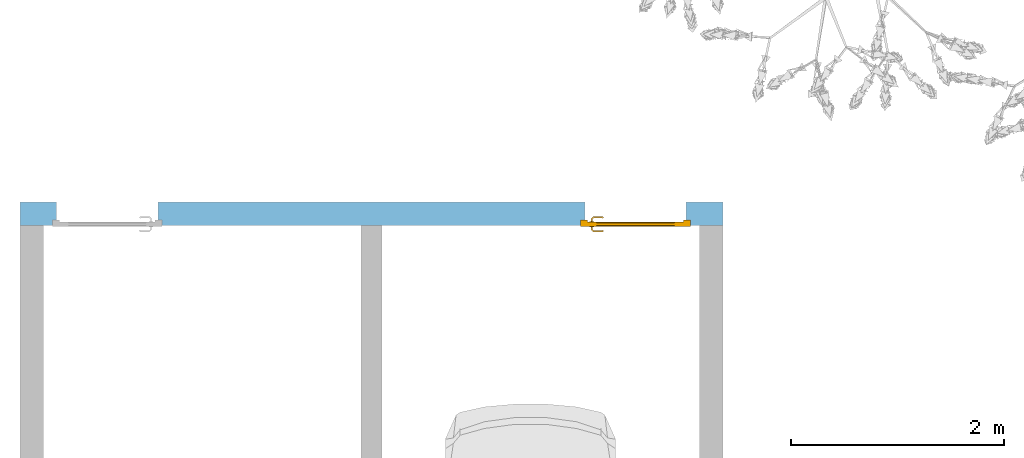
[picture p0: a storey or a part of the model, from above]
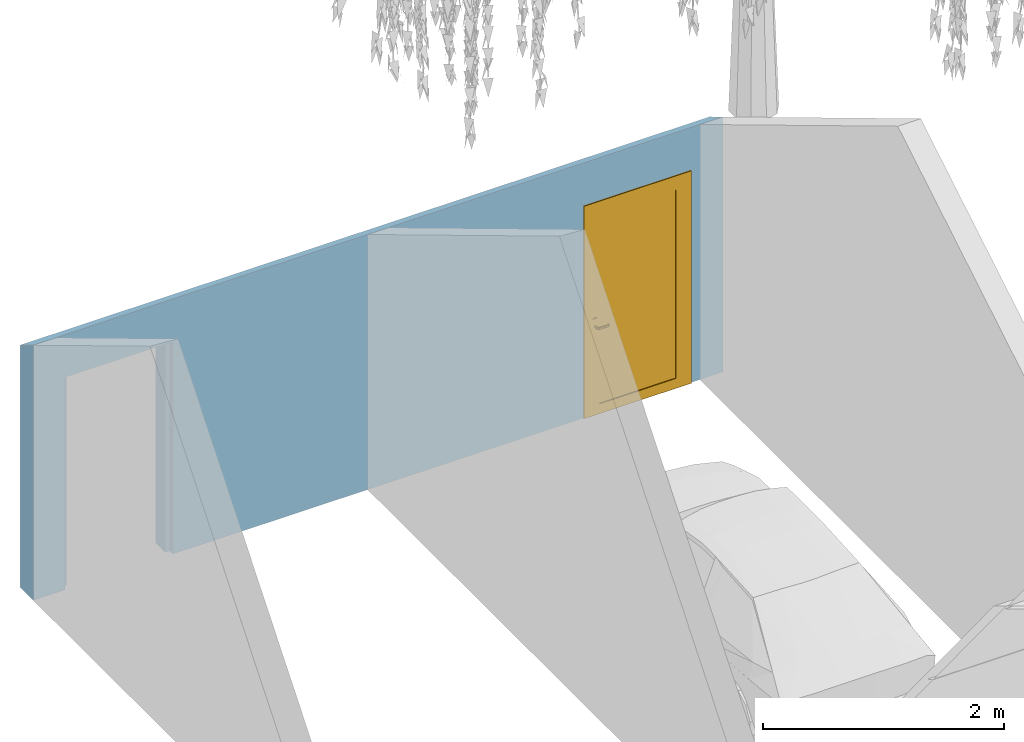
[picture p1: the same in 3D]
Properties of the parts of a building model (IFC2X3)

# File
Description: ViewDefinition [CoordinationView_V2.0]
Time: 2016-03-02T06:42:50
Written by: The EXPRESS Data Manager Version 5.02.0100.07 : 28 Aug 2013
Made in: 20150714_1515(x64) - Exporter 16.3.0.0 - Interface alternative d'export 16.3.0.0
Comment: STEP Physical File produced by: The EXPRESS Data Manager Version 5.02.0100.07 : 28 Aug 2013 * Module: EDMstepFileFactory/EDMstandAlone * Creation date: Wed Mar 02 06:42:50 2016 * Host: St�phaneBertran * Database: C:\Users\STPHAN~1\AppData\Local\Temp\{C8C356D1-8ECD-40BC-B914-F6F8F303F9F7}\ifc * Database version: 5507 * Database creation date: Wed Mar 02 06:42:32 2016 * Schema: IFC2X3 * Model: DataRepository.ifc * Model creation date: Wed Mar 02 06:42:33 2016 * Header model: DataRepository.ifc_HeaderModel * Header model creation date: Wed Mar 02 06:42:33 2016 * EDMuser: sdai-user * EDMgroup: sdai-group * License ID and type: 5605 : Permanent license. Expiry date: * EDMstepFileFactory options: 020000

# IfcProject
LongName: 2 garages

# IfcSite, Surface:224469
RefLatitude: 48, 51, 23, 999633; RefLongitude: 2, 21, 3, 553905; RefElevation: 0 m

# IfcBuilding
Pset_BuildingCommon - NumberOfStoreys: 3

# IfcBuildingStorey (3)
Name | LongName | Elevation (m)
Plan de soubassement | Plan de soubassement | -0.75
Plan du rez de chaussée | Plan du rez de chaussée | 0
Niveau 1 | Niveau 1 | 2.45

# IfcSpace (2)
In: Plan du rez de chaussée
InteriorOrExteriorSpace: INTERNAL
Name | LongName | Reference
1 | Garage 1 | Garage 1 1
2 | Garage 2 | Garage 2 2

# IfcBuildingElementProxy: Bicycle01, Bicycle01:Bicycle01:227164
In: Plan du rez de chaussée
Pset_BuildingElementProxyCommon - Reference: Bicycle01

# IfcBuildingElementProxy: Car01, Car01:Car01:226481
In: 1
Pset_BuildingElementProxyCommon - Reference: Car01

# IfcBuildingElementProxy: Saule pleureur - 6 m, Arbre 3D - Saule pleureur:Saule pleureur - 6 m:225890
In: Plan du rez de chaussée
Pset_BuildingElementProxyCommon - Reference: Saule pleureur - 6 m

# IfcDoor: 93 x 210 - (90), FR_PVC Panneau Plein:93 x 210 - (90):216726
In: Plan du rez de chaussée
Type - OperationType: SINGLE_SWING_LEFT; ParameterTakesPrecedence: no; Sizeable: no; Material: Poignée PVC, PVC Blanc
Type - FR_PVC Panneau Plein:93 x 210 - (90):216726 - PanelOperation: SWINGING
OverallHeight: 2.15 m; OverallWidth: 1.03 m
Pset_DoorCommon - IsExternal: no; Reference: 93 x 210 - (90)

# IfcDoor: 93 x 210 - (90), FR_PVC Panneau Plein:93 x 210 - (90):216636
In: Plan du rez de chaussée
Type - OperationType: SINGLE_SWING_RIGHT; ParameterTakesPrecedence: no; Sizeable: no; Material: Poignée PVC, PVC Blanc
Type - FR_PVC Panneau Plein:93 x 210 - (90):216636 - PanelOperation: SWINGING
OverallHeight: 2.15 m; OverallWidth: 1.03 m
Pset_DoorCommon - IsExternal: no; Reference: 93 x 210 - (90)

# IfcDoor: 96" x 78" (2)
In: Plan du rez de chaussée
Type - ParameterTakesPrecedence: no; Sizeable: no; Classification: B2030410 Overhead Doors (Uniformat); Material: Rubber - Black
OverallHeight: 1.9812 m; OverallWidth: 2.4384 m
Pset_DoorCommon - Reference: 96" x 78"; IsExternal: no
Name (Overhead-Sectional-Flush:96" x 78":...)
216232
216340

# IfcRoof: Toit de base:Toit - 100 mm 2, Toit de base:Toit - 100 mm 2:216761
In: Niveau 1
Pset_RoofCommon - IsExternal: yes; Reference: Toit - 100 mm 2; TotalArea: 61.8782 m2; ProjectedArea: 53.04 m2

# IfcSlab: Sol:Dalle en béton - 250 mm, Sol:Dalle en béton - 250 mm:217332
In: Plan de soubassement
PredefinedType: FLOOR; Material: Maçonnerie - Béton 0.25 m
Pset_SlabCommon - IsExternal: no; LoadBearing: yes; Reference: Dalle en béton - 250 mm; PitchAngle: 0 deg

# IfcSlab: Toit de base:Toit - 100 mm 2 (2)
In: Niveau 1
PredefinedType: ROOF; Material: Toit par défaut 0.1 m
Pset_SlabCommon - IsExternal: yes; Reference: Toit - 100 mm 2; LoadBearing: yes; PitchAngle: 31 deg

# IfcWallStandardCase: Mur de base:Ext.BBM + enduit 22 (4)
In: Plan du rez de chaussée
Type - PredefinedType: STANDARD; Material: Maçonnerie - Enduit 0.02 m, Maçonnerie - Béton 0.2 m
Pset_WallCommon - Reference: Ext.BBM + enduit 22; LoadBearing: no; ExtendToStructure: yes; IsExternal: yes
Name (Mur de base:Ext.BBM + enduit 22:...)
211819
211856
211887
211961

# IfcWallStandardCase: Mur de base:Ext.BBM 20 cm, Mur de base:Ext.BBM 20 cm:212156
In: Plan du rez de chaussée
Type - PredefinedType: STANDARD; Material: Mur par défaut 0.2 m
Pset_WallCommon - LoadBearing: no; ExtendToStructure: yes; IsExternal: yes; Reference: Ext.BBM 20 cm

# IfcWallStandardCase: Mur de base:fond 60 cm (4)
In: Plan de soubassement
Type - PredefinedType: STANDARD; Material: FONDATIONS 0.6 m
Pset_WallCommon - IsExternal: yes; LoadBearing: yes; Reference: fond 60 cm; ExtendToStructure: no
Name (Mur de base:fond 60 cm:...)
218726
218805
218861
218931
